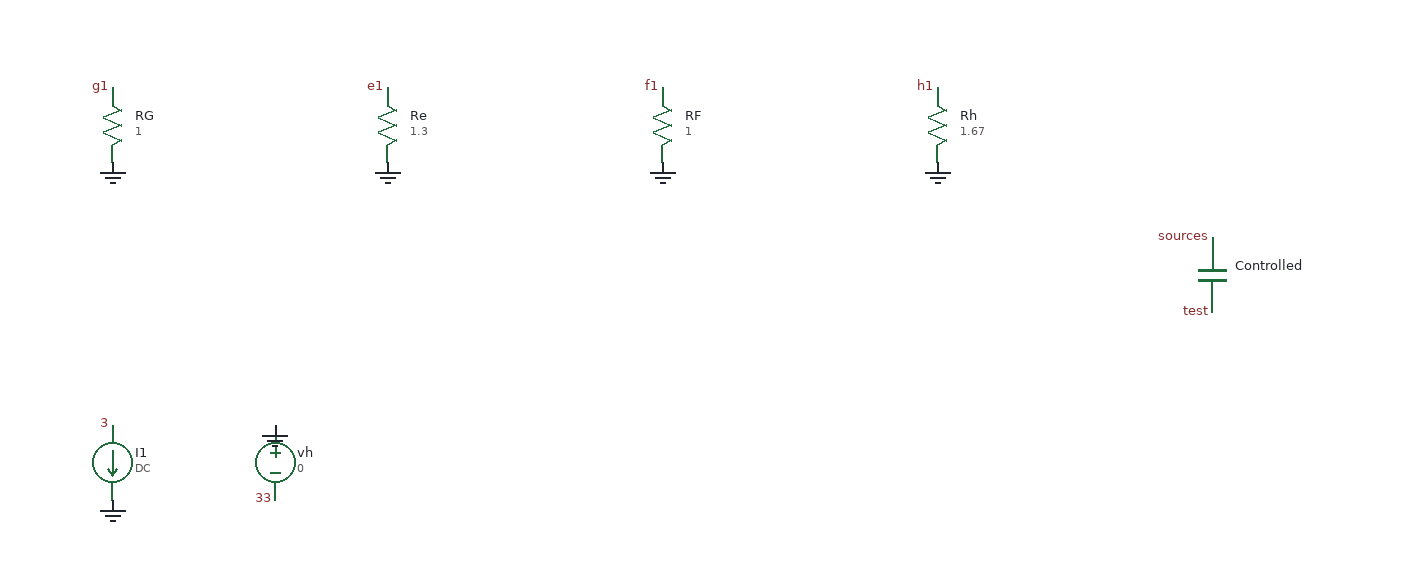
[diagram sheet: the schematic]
v {xschem version=3.4.5 file_version=1.2}
G {}
K {}
V {}
S {}
E {}
C {devices/capa.sym} 1320 -280 0 0 {name=Controlled}
C {devices/res.sym} 440 -400 0 0 {name=RG
value=1}
C {devices/res.sym} 660 -400 0 0 {name=Re
value=1.3}
C {devices/res.sym} 880 -400 0 0 {name=RF
value=1}
C {devices/res.sym} 1100 -400 0 0 {name=Rh
value=1.67}
C {devices/isource.sym} 440 -130 0 0 {name=I1
value=DC}
C {devices/vsource.sym} 570 -130 0 0 {name=vh
value=0}
C {devices/lab_pin.sym} 1320 -310 0 0 {name=l_sources sig_type=std_logic lab=sources}
C {devices/lab_pin.sym} 1320 -250 0 0 {name=l_test sig_type=std_logic lab=test}
C {devices/lab_pin.sym} 440 -430 0 0 {name=l_g1 sig_type=std_logic lab=g1}
C {devices/gnd.sym} 440 -370 0 0 {name=l_0 lab=GND}
C {devices/gnd.sym} 660 -370 0 0 {name=l_0 lab=GND}
C {devices/gnd.sym} 880 -370 0 0 {name=l_0 lab=GND}
C {devices/gnd.sym} 1100 -370 0 0 {name=l_0 lab=GND}
C {devices/gnd.sym} 440 -100 0 0 {name=l_0 lab=GND}
C {devices/gnd.sym} 570 -160 0 0 {name=l_0 lab=GND}
C {devices/lab_pin.sym} 660 -430 0 0 {name=l_e1 sig_type=std_logic lab=e1}
C {devices/lab_pin.sym} 880 -430 0 0 {name=l_f1 sig_type=std_logic lab=f1}
C {devices/lab_pin.sym} 1100 -430 0 0 {name=l_h1 sig_type=std_logic lab=h1}
C {devices/lab_pin.sym} 440 -160 0 0 {name=l_3 sig_type=std_logic lab=3}
C {devices/lab_pin.sym} 570 -100 0 0 {name=l_33 sig_type=std_logic lab=33}
